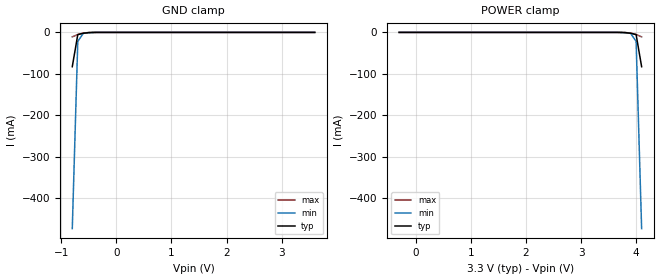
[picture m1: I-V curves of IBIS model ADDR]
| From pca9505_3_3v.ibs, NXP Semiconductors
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[Model]   ADDR
Model_type Input
Vinh=2.31
Vinl=0.99
C_comp   1.7p   1.5p   1.9p
[Temperature Range] 27   85   -40
[Voltage Range]   3.3   3   3.6
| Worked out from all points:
|   GND clamp passes 1 mA (typ) near -0.53 V on its own axis
[GND Clamp]
-800mV    -82.74mA   -473.3mA   -10.75mA
-700mV    -5.302mA   -21.58mA   -5.122mA
-600mV    -2.04mA    -2.358mA   -1.687mA
-300mV    -1.502uA   -7.415uA   -93.17nA
3.6V      65.11pA    250.9pA    47.06pA
[POWER Clamp]
-300mV    65.11pA    250.9pA    47.06pA
3.6V      -1.502uA   -7.415uA   -93.17nA
3.9V      -2.04mA    -2.358mA   -1.687mA
4V        -5.302mA   -21.58mA   -5.122mA
4.1V      -82.74mA   -473.3mA   -10.75mA
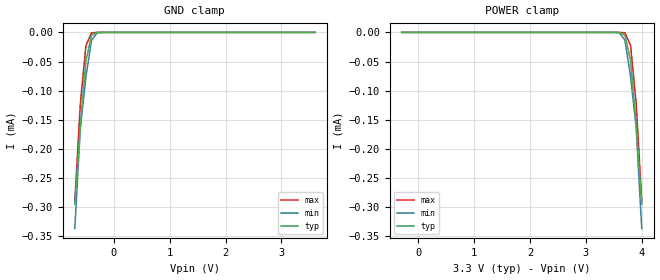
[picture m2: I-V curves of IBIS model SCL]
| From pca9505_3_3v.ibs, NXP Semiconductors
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[Model]   SCL
Model_type Input
Vinh=2.31
Vinl=0.99
C_comp   3.4p   3.2p   3.6p
[Temperature Range] 27   85   -40
[Voltage Range]   3.3   3   3.6
[GND Clamp]
-700mV    -295uA     -337uA     -289.5uA
-600mV    -158.8uA   -164.3uA   -122uA
-500mV    -48.62uA   -75.94uA   -22.35uA
-400mV    -4.926uA   -13.83uA   -710.6nA
-300mV    -138.4nA   -722.3nA   -7.551nA
3.6V      8.544pA    24.57pA    7.213pA
[POWER Clamp]
-300mV    8.544pA    24.57pA    7.213pA
3.6V      -138.4nA   -722.3nA   -7.551nA
3.7V      -4.926uA   -13.83uA   -710.6nA
3.8V      -48.62uA   -75.94uA   -22.35uA
3.9V      -158.8uA   -164.3uA   -122uA
4V        -295uA     -337uA     -289.5uA
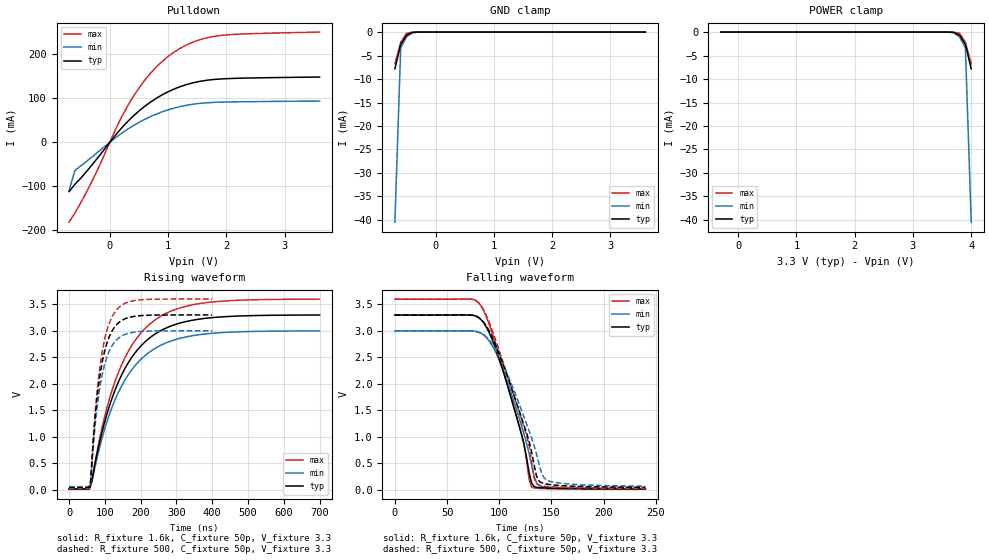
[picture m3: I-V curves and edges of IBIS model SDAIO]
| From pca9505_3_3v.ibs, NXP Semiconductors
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[Model]   SDAIO
Model_type I/O_open_drain
Vinh=2.31
Vinl=0.99
Vref=3.3
Vmeas=1.65
Rref=1.6k
Cref=50p
C_comp   7p   6.8p   7.2p
[Temperature Range] 27   85   -40
[Voltage Range]   3.3   3   3.6
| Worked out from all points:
|   slope of the pulldown table from 0 to 0.495 V, typ, clamps not added: 7.03 ohm
|   GND clamp passes 1 mA (typ) near -0.52 V on its own axis
|   falling waveform, R_fixture 1.6k, C_fixture 50p, V_fixture 3.3: 20-80 % time 28.6ns typ, 28.4ns min, 30.3ns max; typ from 3.3 V to 0.013 V
|   falling waveform, R_fixture 500, C_fixture 50p, V_fixture 3.3: 20-80 % time 32.8ns typ, 33.3ns min, 33.7ns max; typ from 3.3 V to 0.043 V
|   rising waveform, R_fixture 1.6k, C_fixture 50p, V_fixture 3.3: 20-80 % time 113ns typ, 114ns min, 113ns max; typ from 0.012 V to 3.3 V
|   rising waveform, R_fixture 500, C_fixture 50p, V_fixture 3.3: 20-80 % time 35.4ns typ, 35.5ns min, 35.3ns max; typ from 0.038 V to 3.3 V
[Pulldown]
-700mV    -112.1mA   -109.5mA   -181.5mA
-600mV    -95.67mA   -64.43mA   -160.8mA
-300mV    -50.42mA   -32.67mA   -86.89mA
100mV     16.68mA    10.42mA    29.78mA
300mV     46.23mA    29.16mA    81.3mA
600mV     81.66mA    52.05mA    141mA
800mV     100mA      64.03mA    171.1mA
1V        114.6mA    73.55mA    194.7mA
1.4V      134mA      85.79mA    225.9mA
1.8V      142.7mA    90.53mA    240.6mA
2.3V      145.5mA    91.97mA    245.8mA
3.6V      148.1mA    93.58mA    250.1mA
[GND Clamp]
-700mV    -7.829mA   -40.49mA   -6.738mA
-600mV    -2.622mA   -3.361mA   -2.171mA
-500mV    -650.2uA   -1.024mA   -275.9uA
-400mV    -53.1uA    -156.9uA   -7.365uA
-300mV    -1.415uA   -7.428uA   -76.94nA
3.6V      194.8pA    194.8pA    194.8pA
[POWER Clamp]
-300mV    123.7pA    160.1pA    123.7pA
3.6V      -1.415uA   -7.428uA   -76.79nA
3.7V      -53.1uA    -156.9uA   -7.365uA
3.8V      -650.2uA   -1.024mA   -275.9uA
3.9V      -2.622mA   -3.361mA   -2.171mA
4V        -7.829mA   -40.49mA   -6.738mA
[Falling Waveform]
R_fixture=1.6k
C_fixture=50p
V_fixture=3.3
V_fixture_min=3
V_fixture_max=3.6
0s        3.3V       3V         3.6V
82.42ns   3.215V     2.956V     3.475V
92.12ns   2.889V     2.757V     3.024V
104.2ns   2.202V     2.237V     2.238V
123.6ns   862.4mV    1.053V     865.9mV
128.5ns   332.5mV    687.8mV    203.5mV
130.9ns   123.7mV    466.9mV    49.13mV
135.8ns   43.36mV    125.3mV    25.43mV
140.6ns   34.19mV    58.97mV    20.12mV
240ns     13.44mV    19.99mV    8.03mV
[Falling Waveform]
R_fixture=500
C_fixture=50p
V_fixture=3.3
V_fixture_min=3
V_fixture_max=3.6
0s        3.3V       3V         3.6V
82.42ns   3.221V     2.959V     3.482V
92.12ns   2.931V     2.783V     3.075V
106.7ns   2.206V     2.235V     2.229V
126.1ns   1.076V     1.247V     1.027V
133.3ns   470mV      836.1mV    220.4mV
135.8ns   250.8mV    662.5mV    108.5mV
140.6ns   129.1mV    309mV      74.33mV
147.9ns   96.86mV    159.5mV    55.87mV
240ns     43.31mV    64.4mV     25.86mV
[Rising Waveform]
R_fixture=1.6k
C_fixture=50p
V_fixture=3.3
V_fixture_min=3
V_fixture_max=3.6
0s        11.96mV    17.46mV    7.254mV
56.57ns   11.85mV    18.77mV    7.255mV
63.64ns   164.6mV    129.6mV    156.4mV
98.99ns   1.263V     1.132V     1.366V
134.3ns   1.978V     1.786V     2.151V
176.8ns   2.513V     2.277V     2.739V
233.3ns   2.907V     2.638V     3.17V
297ns     3.12V      2.834V     3.404V
374.7ns   3.231V     2.936V     3.524V
700ns     3.299V     2.999V     3.599V
[Rising Waveform]
R_fixture=500
C_fixture=50p
V_fixture=3.3
V_fixture_min=3
V_fixture_max=3.6
0s        38.26mV    55.73mV    23.23mV
56.57ns   40.92mV    63.58mV    23.23mV
60.61ns   179mV      153.2mV    112.5mV
72.73ns   1.353V     1.198V     1.428V
80.81ns   1.881V     1.685V     2.017V
88.89ns   2.266V     2.041V     2.448V
105.1ns   2.751V     2.49V      2.989V
129.3ns   3.088V     2.803V     3.365V
189.9ns   3.28V      2.982V     3.578V
400ns     3.3V       3V         3.6V
[Ramp]
R_load=1.6k
dV/dt_r   1.973E+0/2.652E-9   1.968E+0/3.052E-9   1.976E+0/2.329E-9
dV/dt_f   1.972E+0/2.729E-8   1.967E+0/2.902E-8   1.976E+0/2.687E-8
|[End   SDAIO
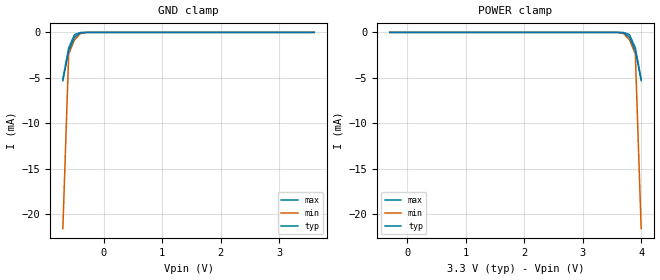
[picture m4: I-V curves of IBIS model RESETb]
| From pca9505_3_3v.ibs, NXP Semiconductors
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[Model]   RESETb
Model_type Input
Vinh=2.31
Vinl=0.99
C_comp   1.7p   1.5p   1.9p
[Temperature Range] 27   85   -40
[Voltage Range]   3.3   3   3.6
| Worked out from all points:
|   GND clamp passes 1 mA (typ) near -0.53 V on its own axis
[GND Clamp]
-700mV    -5.302mA   -21.58mA   -5.122mA
-600mV    -2.04mA    -2.358mA   -1.687mA
-500mV    -525.2uA   -816.9uA   -228.9uA
-400mV    -48.21uA   -135uA     -7.763uA
-200mV    -27.28nA   -200nA     -811.9pA
3.6V      65.11pA    250.9pA    47.06pA
[POWER Clamp]
-300mV    65.11pA    250.9pA    47.06pA
3.5V      -27.28nA   -200nA     -811.9pA
3.7V      -48.21uA   -135uA     -7.763uA
3.8V      -525.2uA   -816.9uA   -228.9uA
3.9V      -2.04mA    -2.358mA   -1.687mA
4V        -5.302mA   -21.58mA   -5.122mA
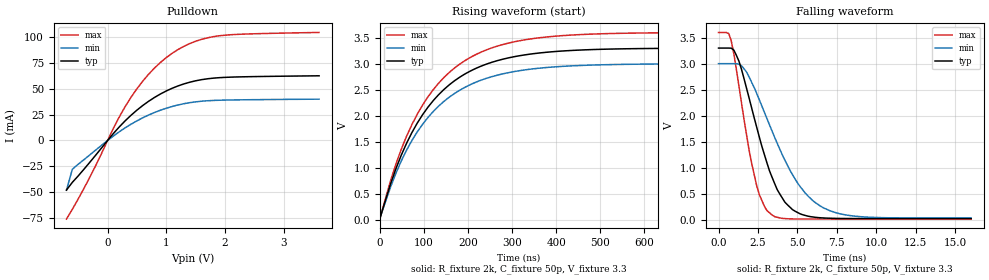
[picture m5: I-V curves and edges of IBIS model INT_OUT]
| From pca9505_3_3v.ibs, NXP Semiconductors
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[Model]   INT_OUT
Model_type Open_drain
Vref=3.3
Vmeas=1.65
Rref=2k
Cref=50p
C_comp   5.2p   5p   5.4p
[Temperature Range] 27   85   -40
[Voltage Range]   3.3   3   3.6
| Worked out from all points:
|   slope of the pulldown table from 0 to 0.495 V, typ, clamps not added: 16.9 ohm
|   falling waveform, R_fixture 2k, C_fixture 50p, V_fixture 3.3: 20-80 % time 1.91ns typ, 2.75ns min, 1.23ns max; typ from 3.3 V to 0.023 V
|   rising waveform, R_fixture 2k, C_fixture 50p, V_fixture 3.3: 20-80 % time 141ns typ, 142ns min, 141ns max; typ from 0.023 V to 3.3 V
[Pulldown]
-700mV    -48.11mA   -48.26mA   -76.24mA
-600mV    -40.62mA   -27.97mA   -66.82mA
-300mV    -20.97mA   -13.85mA   -35.4mA
100mV     6.864mA    4.38mA     11.98mA
300mV     19.12mA    12.3mA     32.94mA
600mV     34.01mA    22.05mA    57.69mA
800mV     41.81mA    27.21mA    70.38mA
1V        48.09mA    31.34mA    80.47mA
1.4V      56.58mA    36.72mA    94.11mA
1.8V      60.51mA    38.86mA    100.8mA
2.3V      61.79mA    39.48mA    103.2mA
3.6V      62.78mA    40.11mA    104.8mA
[Falling Waveform]
R_fixture=2k
C_fixture=50p
V_fixture=3.3
V_fixture_min=3
V_fixture_max=3.6
0s        3.3V       3V         3.6V
646.5ps   3.3V       3V         3.579V
969.7ps   3.261V     3V         3.192V
1.293ns   3.049V     2.99V      2.571V
1.939ns   2.338V     2.742V     1.334V
2.424ns   1.773V     2.425V     647.3mV
3.394ns   816.3mV    1.704V     92.6mV
4.687ns   195.7mV    867.1mV    16.96mV
6.949ns   31.27mV    187.8mV    14.48mV
16ns      23.28mV    33.29mV    14.47mV
[Rising Waveform]
R_fixture=2k
C_fixture=50p
V_fixture=3.3
V_fixture_min=3
V_fixture_max=3.6
0s        23.28mV    33.22mV    14.47mV
24.24ns   687.7mV    628.2mV    749mV
48.48ns   1.24V      1.128V     1.353V
72.73ns   1.676V     1.524V     1.83V
109.1ns   2.164V     1.966V     2.363V
169.7ns   2.674V     2.43V      2.919V
254.5ns   3.028V     2.752V     3.305V
351.5ns   3.195V     2.904V     3.487V
484.8ns   3.272V     2.974V     3.57V
1.2us     3.3V       3V         3.6V
[Ramp]
R_load=2k
dV/dt_r   1.966E+0/2.660E-9   1.958E+0/2.945E-9   1.972E+0/2.355E-9
dV/dt_f   1.966E+0/1.680E-10   1.958E+0/2.213E-10   1.972E+0/7.973E-11
|[End   INT_OUT
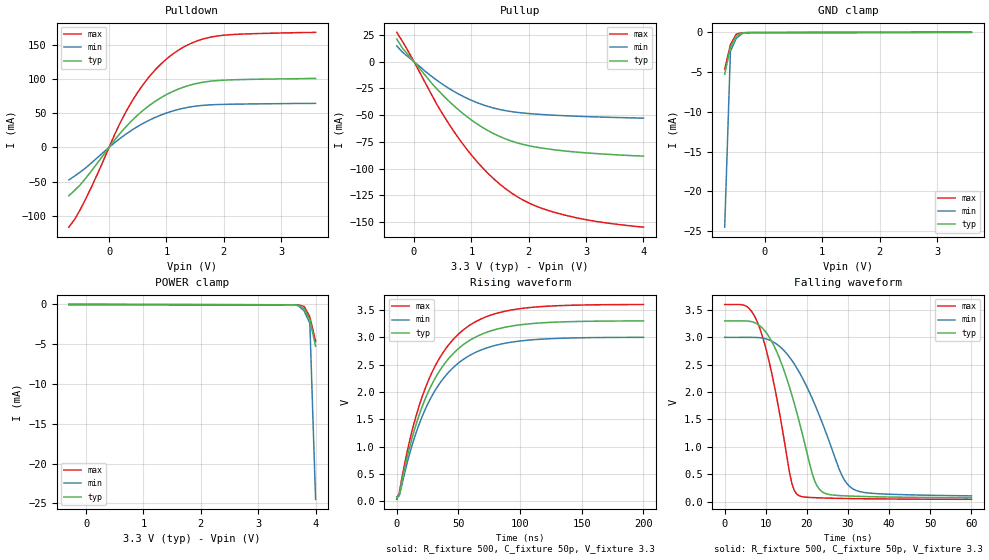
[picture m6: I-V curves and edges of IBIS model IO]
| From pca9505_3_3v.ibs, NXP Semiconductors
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[Model]   IO
Model_type I/O
Vinh=2.31
Vinl=0.99
Vref=3.3
Vmeas=1.65
Rref=500
Cref=50p
C_comp   7p   6.8p   7.2p
[Temperature Range] 27   85   -40
[Voltage Range]   3.3   3   3.6
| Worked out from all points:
|   slope of the pulldown table from 0 to 0.495 V, typ, clamps not added: 10.6 ohm
|   slope of the pullup table from 0 to 0.495 V, typ, clamps not added: 16 ohm
|   GND clamp passes 1 mA (typ) near -0.54 V on its own axis
|   falling waveform, R_fixture 500, C_fixture 50p, V_fixture 3.3: 20-80 % time 7.44ns typ, 9.71ns min, 5.59ns max; typ from 3.3 V to 0.069 V
|   rising waveform, R_fixture 500, C_fixture 50p, V_fixture 3.3: 20-80 % time 36.2ns typ, 36.4ns min, 36ns max; typ from 0.058 V to 3.3 V
[Pullup]
-300mV    21.04mA    14.72mA    27.4mA
-200mV    12.51mA    8.806mA    18.81mA
300mV     -19.68mA   -13.51mA   -30.19mA
500mV     -31.23mA   -21.25mA   -49.11mA
700mV     -41.51mA   -27.98mA   -65.68mA
1.1V      -58.31mA   -38.39mA   -93.63mA
1.3V      -64.85mA   -42.09mA   -105mA
1.6V      -72.39mA   -45.91mA   -119mA
2V        -78.65mA   -48.54mA   -132.2mA
2.5V      -82.79mA   -50.28mA   -141.7mA
3.1V      -85.72mA   -51.57mA   -148.8mA
4V        -88.4mA    -52.87mA   -154.8mA
[Pulldown]
-700mV    -70.45mA   -47.39mA   -116.3mA
-600mV    -62.65mA   -41.8mA    -105mA
-400mV    -44.32mA   -29.49mA   -74mA
-200mV    -22.52mA   -14.7mA    -38.52mA
100mV     10.98mA    7.008mA    19.17mA
400mV     39.25mA    25.32mA    67.24mA
700mV     60.98mA    39.62mA    103mA
900mV     72.22mA    47.04mA    121.2mA
1.1V      81.12mA    52.85mA    135.4mA
1.5V      92.71mA    60.03mA    154.2mA
1.9V      97.53mA    62.5mA     162.6mA
3.6V      100.5mA    64.19mA    167.8mA
[GND Clamp]
-700mV    -5.259mA   -24.49mA   -4.618mA
-600mV    -1.894mA   -2.376mA   -1.549mA
-500mV    -516.6uA   -788.3uA   -247.3uA
-400mV    -81.15uA   -158.5uA   -46.94uA
-200mV    -34.98uA   -32.14uA   -37.95uA
3.6V      2.992nA    1.983nA    1.985nA
[POWER Clamp]
-300mV    1.292nA    1.982nA    1.874nA
3.5V      -34.98uA   -32.14uA   -37.95uA
3.7V      -81.15uA   -158.5uA   -46.94uA
3.8V      -516.6uA   -788.3uA   -247.3uA
3.9V      -1.894mA   -2.376mA   -1.549mA
4V        -5.259mA   -24.49mA   -4.618mA
[Falling Waveform]
R_fixture=500
C_fixture=50p
V_fixture=3.3
V_fixture_min=3
V_fixture_max=3.6
0s        3.3V       3V         3.6V
5.455ns   3.298V     3V         3.56V
8.485ns   3.215V     2.994V     3.175V
12.73ns   2.726V     2.872V     1.865V
15.76ns   2.091V     2.639V     534.2mV
17.58ns   1.615V     2.434V     133.3mV
22.42ns   291.1mV    1.683V     69.65mV
28.48ns   107.4mV    481.2mV    57.48mV
30.91ns   99.62mV    245.3mV    54.48mV
60ns      68.93mV    104.6mV    41.09mV
[Rising Waveform]
R_fixture=500
C_fixture=50p
V_fixture=3.3
V_fixture_min=3
V_fixture_max=3.6
0s        58.49mV    83.23mV    36.42mV
2.02ns    115.4mV    99.73mV    156.9mV
6.061ns   570.1mV    487.4mV    651.7mV
12.12ns   1.134V     1.004V     1.265V
24.24ns   1.936V     1.739V     2.134V
38.38ns   2.506V     2.264V     2.749V
54.55ns   2.874V     2.604V     3.145V
72.73ns   3.089V     2.803V     3.376V
98.99ns   3.224V     2.929V     3.519V
200ns     3.298V     2.998V     3.598V
[Ramp]
R_load=500
dV/dt_r   9.548E-3/2.222E-9   8.569E-3/2.525E-9   1.052E-2/1.828E-9
dV/dt_f   1.939E+0/4.604E-9   1.738E+0/6.223E-9   2.135E+0/3.448E-9
|[End   IO
